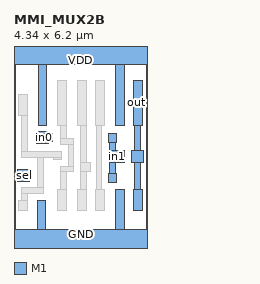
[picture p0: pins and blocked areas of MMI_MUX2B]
MACRO MMI_MUX2B
	CLASS CORE ;
	FOREIGN MMI_MUX2B 0 0 ;
	SIZE 4.34 BY 6.2 ;
	SYMMETRY X Y ;
	SITE CORE1 ;
	PIN out
		DIRECTION output ;
		USE SIGNAL ;
		PORT
			LAYER M1 ;
			RECT 3.9 3.815 4.18 5.285 ;
			LAYER M1 ;
			RECT 3.945 2.98 4.14 3.815 ;
			LAYER M1 ;
			RECT 3.84 2.6 4.22 2.98 ;
			LAYER M1 ;
			RECT 3.945 1.725 4.14 2.6 ;
			LAYER M1 ;
			RECT 3.9 1.025 4.18 1.725 ;
		END
		AntennaDiffArea 0.91245 ;
	END out
	PIN sel
		DIRECTION input ;
		USE SIGNAL ;
		PORT
			LAYER M1 ;
			RECT 0.12 1.98 0.5 2.36 ;
		END
		AntennaGateArea 0.51975 ;
	END sel
	PIN in1
		DIRECTION input ;
		USE SIGNAL ;
		PORT
			LAYER M1 ;
			RECT 3.07 3.26 3.35 3.54 ;
			LAYER M1 ;
			RECT 3.115 2.98 3.305 3.26 ;
			LAYER M1 ;
			RECT 3.115 2.6 3.6 2.98 ;
			LAYER M1 ;
			RECT 3.115 2.225 3.305 2.6 ;
			LAYER M1 ;
			RECT 3.07 1.945 3.35 2.225 ;
		END
		AntennaGateArea 0.3465 ;
	END in1
	PIN GND
		DIRECTION inout ;
		USE GROUND ;
		PORT
			LAYER M1 ;
			RECT 0.755 0.42 1.035 1.34 ;
			LAYER M1 ;
			RECT 3.31 0.42 3.59 1.725 ;
			LAYER M1 ;
			RECT 0 -0.42 4.34 0.42 ;
		END
	END GND
	PIN VDD
		DIRECTION inout ;
		USE POWER ;
		PORT
			LAYER M1 ;
			RECT 0 5.78 4.34 6.62 ;
			LAYER M1 ;
			RECT 0.795 3.815 1.075 5.78 ;
			LAYER M1 ;
			RECT 3.31 3.815 3.59 5.78 ;
		END
	END VDD
	PIN in0
		DIRECTION input ;
		USE SIGNAL ;
		PORT
			LAYER M1 ;
			RECT 0.74 3.555 1.12 3.6 ;
			LAYER M1 ;
			RECT 0.74 3.275 1.24 3.555 ;
			LAYER M1 ;
			RECT 0.74 3.22 1.12 3.275 ;
		END
		AntennaGateArea 0.3465 ;
	END in0
	OBS
		LAYER M1 ;
		RECT 0.16 4.12 0.44 4.82 ;
		LAYER M1 ;
		RECT 0.245 2.955 0.435 4.12 ;
		LAYER M1 ;
		RECT 1.435 3.815 1.715 5.285 ;
		LAYER M1 ;
		RECT 2.07 3.815 2.35 5.285 ;
		LAYER M1 ;
		RECT 2.66 3.815 2.94 5.285 ;
		LAYER M1 ;
		RECT 1.52 3.37 1.715 3.815 ;
		LAYER M1 ;
		RECT 1.52 3.175 1.955 3.37 ;
		LAYER M1 ;
		RECT 1.285 2.955 1.565 2.96 ;
		LAYER M1 ;
		RECT 0.245 2.76 1.565 2.955 ;
		LAYER M1 ;
		RECT 0.775 1.78 0.97 2.76 ;
		LAYER M1 ;
		RECT 1.285 2.68 1.565 2.76 ;
		LAYER M1 ;
		RECT 1.765 2.475 1.955 3.175 ;
		LAYER M1 ;
		RECT 0.245 1.585 0.97 1.78 ;
		LAYER M1 ;
		RECT 1.52 2.285 1.955 2.475 ;
		LAYER M1 ;
		RECT 2.16 2.59 2.35 3.815 ;
		LAYER M1 ;
		RECT 2.16 2.31 2.48 2.59 ;
		LAYER M1 ;
		RECT 1.52 1.725 1.715 2.285 ;
		LAYER M1 ;
		RECT 2.16 1.725 2.35 2.31 ;
		LAYER M1 ;
		RECT 2.68 1.725 2.87 3.815 ;
		LAYER M1 ;
		RECT 0.245 1.34 0.435 1.585 ;
		LAYER M1 ;
		RECT 0.16 1.025 0.44 1.34 ;
		LAYER M1 ;
		RECT 1.435 1.025 1.715 1.725 ;
		LAYER M1 ;
		RECT 2.07 1.025 2.35 1.725 ;
		LAYER M1 ;
		RECT 2.66 1.025 2.94 1.725 ;
	END
END MMI_MUX2B
